VERSION 5.8 ;
BUSBITCHARS "[]" ;
DIVIDERCHAR "/" ;

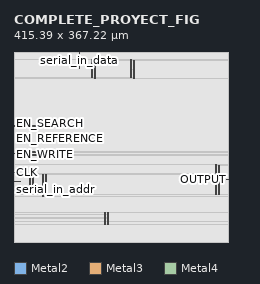
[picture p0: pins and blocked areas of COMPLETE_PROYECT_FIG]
MACRO COMPLETE_PROYECT_FIG
  CLASS BLOCK ;
  FOREIGN COMPLETE_PROYECT_FIG 0 0 ;
  ORIGIN 0 0 ;
  SIZE 415.390 BY 367.220 ;
  SYMMETRY X Y ;
  PIN EN_WRITE
    DIRECTION INPUT ;
    USE SIGNAL ;
    PORT
      LAYER Metal2 ;
        RECT 0.000 184.945 0.605 185.345 ;
    END
  END EN_WRITE
  PIN EN_REFERENCE
    DIRECTION INPUT ;
    USE SIGNAL ;
    PORT
      LAYER Metal2 ;
        RECT 0.000 199.345 0.605 199.745 ;
    END
  END EN_REFERENCE
  PIN EN_SEARCH
    DIRECTION INPUT ;
    USE SIGNAL ;
    PORT
      LAYER Metal2 ;
        RECT 0.000 213.745 0.605 214.145 ;
    END
  END EN_SEARCH
  PIN reset
    DIRECTION INPUT ;
    USE SIGNAL ;
    PORT
      LAYER Metal2 ;
        RECT 0.000 170.640 2.000 170.840 ;
    END
  END reset
  PIN CLK
    DIRECTION INPUT ;
    USE SIGNAL ;
    PORT
      LAYER Metal2 ;
        RECT 0.000 133.430 3.100 133.640 ;
    END
  END CLK
  PIN serial_in_addr
    DIRECTION INPUT ;
    USE SIGNAL ;
    PORT
      LAYER Metal2 ;
        RECT 0.000 116.555 12.040 116.955 ;
    END
  END serial_in_addr
  PIN OUTPUT
    DIRECTION OUTPUT ;
    USE SIGNAL ;
    PORT
      LAYER Metal3 ;
        RECT 410.515 121.145 415.390 121.545 ;
    END
  END OUTPUT
  PIN serial_in_data
    DIRECTION INPUT ;
    USE SIGNAL ;
    PORT
      LAYER Metal3 ;
        RECT 126.860 334.715 127.260 367.220 ;
    END
  END serial_in_data
  PIN VEVAL_IN
    DIRECTION INPUT ;
    USE ANALOG ;
    PORT
      LAYER Metal2 ;
        RECT 0.000 224.155 63.055 224.555 ;
    END
  END VEVAL_IN
  PIN VDD
    DIRECTION INOUT ;
    USE POWER ;
    PORT
      LAYER Metal4 ;
        RECT 174.210 33.705 176.410 38.795 ;
        RECT 174.210 39.135 176.190 45.120 ;
        RECT 174.210 46.865 176.190 52.680 ;
        RECT 174.210 52.970 176.190 56.825 ;
        RECT 55.105 88.395 57.305 92.250 ;
        RECT 55.105 94.265 57.305 97.410 ;
        RECT 55.105 97.410 57.085 99.810 ;
        RECT 55.105 100.100 57.085 107.370 ;
        RECT 55.105 107.660 57.085 109.640 ;
        RECT 55.105 109.640 57.305 130.825 ;
        RECT 29.800 100.995 32.000 131.675 ;
        RECT 388.775 91.305 390.975 148.855 ;
        RECT 17.065 166.445 55.305 168.645 ;
        RECT 148.880 317.120 151.080 351.990 ;
        RECT 224.480 317.120 226.680 351.990 ;
    END
  END VDD
  PIN VSS
    DIRECTION INOUT ;
    USE GROUND ;
    PORT
      LAYER Metal4 ;
        RECT 180.410 33.295 182.610 38.940 ;
        RECT 180.410 38.940 182.430 57.235 ;
        RECT 61.305 87.985 63.505 104.130 ;
        RECT 61.725 104.130 63.505 110.060 ;
        RECT 61.305 110.060 63.505 130.415 ;
        RECT 36.000 100.585 38.200 132.085 ;
        RECT 394.975 90.895 397.175 148.445 ;
        RECT 16.655 172.645 55.715 174.845 ;
        RECT 155.080 316.710 157.280 351.580 ;
        RECT 230.860 316.710 232.880 333.745 ;
        RECT 230.680 333.745 232.880 351.580 ;
    END
  END VSS
  OBS
    LAYER Metal1 ;
      RECT 0.000 0.000 415.390 367.220 ;
    LAYER Metal2 ;
      RECT 0.000 0.000 415.390 116.305 ;
      RECT 12.290 116.305 415.390 117.205 ;
      RECT 0.000 117.205 415.390 133.180 ;
      RECT 3.350 133.180 415.390 133.890 ;
      RECT 0.000 133.890 415.390 170.390 ;
      RECT 2.250 170.390 415.390 171.090 ;
      RECT 0.000 171.090 415.390 184.695 ;
      RECT 0.855 184.695 415.390 185.595 ;
      RECT 0.000 185.595 415.390 199.095 ;
      RECT 0.855 199.095 415.390 199.995 ;
      RECT 0.000 199.995 415.390 213.495 ;
      RECT 0.855 213.495 415.390 214.395 ;
      RECT 0.000 214.395 415.390 223.905 ;
      RECT 63.305 223.905 415.390 224.805 ;
      RECT 0.000 224.805 415.390 367.220 ;
    LAYER Metal3 ;
      RECT 0.000 0.000 415.390 120.895 ;
      RECT 0.000 120.895 410.265 121.795 ;
      RECT 0.000 121.795 415.390 334.465 ;
      RECT 0.000 334.465 126.610 367.220 ;
      RECT 127.510 334.465 415.390 367.220 ;
    LAYER Metal4 ;
      RECT 0.000 0.000 415.390 33.295 ;
      RECT 0.000 33.295 180.410 33.705 ;
      RECT 0.000 33.705 174.210 38.795 ;
      RECT 176.410 33.705 180.410 38.795 ;
      RECT 182.610 33.295 415.390 38.940 ;
      RECT 0.000 38.795 180.410 39.135 ;
      RECT 0.000 39.135 174.210 45.120 ;
      RECT 176.190 39.135 180.410 45.120 ;
      RECT 0.000 45.120 180.410 46.865 ;
      RECT 0.000 46.865 174.210 52.680 ;
      RECT 176.190 46.865 180.410 52.680 ;
      RECT 0.000 52.680 180.410 52.970 ;
      RECT 0.000 52.970 174.210 56.825 ;
      RECT 176.190 52.970 180.410 56.825 ;
      RECT 0.000 56.825 180.410 57.235 ;
      RECT 182.430 38.940 415.390 57.235 ;
      RECT 0.000 57.235 415.390 87.985 ;
      RECT 0.000 87.985 61.305 88.395 ;
      RECT 63.505 87.985 415.390 90.895 ;
      RECT 63.505 90.895 394.975 91.305 ;
      RECT 0.000 88.395 55.105 92.250 ;
      RECT 57.305 88.395 61.305 92.250 ;
      RECT 0.000 92.250 61.305 94.265 ;
      RECT 57.305 94.265 61.305 97.410 ;
      RECT 0.000 94.265 55.105 99.810 ;
      RECT 57.085 97.410 61.305 99.810 ;
      RECT 0.000 99.810 61.305 100.100 ;
      RECT 0.000 100.100 55.105 100.585 ;
      RECT 0.000 100.585 36.000 100.995 ;
      RECT 57.085 100.100 61.305 104.130 ;
      RECT 38.200 100.585 55.105 107.370 ;
      RECT 57.085 104.130 61.725 107.370 ;
      RECT 38.200 107.370 61.725 107.660 ;
      RECT 57.085 107.660 61.725 109.640 ;
      RECT 57.305 109.640 61.725 110.060 ;
      RECT 57.305 110.060 61.305 130.415 ;
      RECT 63.505 91.305 388.775 130.415 ;
      RECT 38.200 107.660 55.105 130.825 ;
      RECT 57.305 130.415 388.775 130.825 ;
      RECT 0.000 100.995 29.800 131.675 ;
      RECT 32.000 100.995 36.000 131.675 ;
      RECT 0.000 131.675 36.000 132.085 ;
      RECT 38.200 130.825 388.775 132.085 ;
      RECT 390.975 91.305 394.975 148.445 ;
      RECT 397.175 90.895 415.390 148.445 ;
      RECT 0.000 132.085 388.775 148.855 ;
      RECT 390.975 148.445 415.390 148.855 ;
      RECT 0.000 148.855 415.390 166.445 ;
      RECT 0.000 166.445 17.065 168.645 ;
      RECT 55.305 166.445 415.390 168.645 ;
      RECT 0.000 168.645 415.390 172.645 ;
      RECT 0.000 172.645 16.655 174.845 ;
      RECT 55.715 172.645 415.390 174.845 ;
      RECT 0.000 174.845 415.390 316.710 ;
      RECT 0.000 316.710 155.080 317.120 ;
      RECT 157.280 316.710 230.860 317.120 ;
      RECT 226.680 317.120 230.860 333.745 ;
      RECT 151.080 317.120 155.080 351.580 ;
      RECT 157.280 317.120 224.480 351.580 ;
      RECT 226.680 333.745 230.680 351.580 ;
      RECT 232.880 316.710 415.390 351.580 ;
      RECT 0.000 317.120 148.880 351.990 ;
      RECT 151.080 351.580 224.480 351.990 ;
      RECT 226.680 351.580 415.390 351.990 ;
      RECT 0.000 351.990 415.390 367.220 ;
  END
END COMPLETE_PROYECT_FIG

END LIBRARY
